VERSION 5.7 ;
  NOWIREEXTENSIONATPIN ON ;
  DIVIDERCHAR "/" ;
  BUSBITCHARS "[]" ;
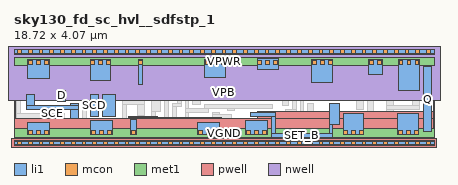
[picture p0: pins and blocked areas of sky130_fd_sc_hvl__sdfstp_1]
MACRO sky130_fd_sc_hvl__sdfstp_1
  CLASS BLOCK ;
  FOREIGN sky130_fd_sc_hvl__sdfstp_1 ;
  ORIGIN 0.000 0.000 ;
  SIZE 18.720 BY 4.070 ;
  PIN CLK
    ANTENNAGATEAREA 0.585000 ;
    PORT
      LAYER li1 ;
        RECT 3.965 1.175 4.525 2.150 ;
    END
  END CLK
  PIN D
    ANTENNAGATEAREA 0.420000 ;
    PORT
      LAYER li1 ;
        RECT 1.945 1.845 2.275 2.355 ;
    END
  END D
  PIN SCD
    ANTENNAGATEAREA 0.420000 ;
    PORT
      LAYER li1 ;
        RECT 3.420 1.175 3.750 2.150 ;
    END
  END SCD
  PIN SCE
    ANTENNAGATEAREA 0.840000 ;
    PORT
      LAYER li1 ;
        RECT 0.565 1.665 0.895 2.165 ;
        RECT 2.525 1.665 2.890 1.780 ;
        RECT 0.565 1.495 2.890 1.665 ;
        RECT 2.525 1.095 2.890 1.495 ;
    END
  END SCE
  PIN SET_B
    ANTENNAGATEAREA 0.840000 ;
    PORT
      LAYER li1 ;
        RECT 10.535 1.175 11.635 1.345 ;
        RECT 11.465 0.435 11.635 1.175 ;
        RECT 14.045 0.810 14.520 1.760 ;
        RECT 14.045 0.435 14.215 0.810 ;
        RECT 11.465 0.265 14.215 0.435 ;
    END
  END SET_B
  PIN VGND
    USE GROUND ;
    PORT
      LAYER li1 ;
        RECT 0.620 0.365 1.570 0.915 ;
        RECT 3.420 0.365 4.370 0.995 ;
        RECT 5.200 0.365 5.450 1.055 ;
        RECT 8.200 0.365 9.150 0.925 ;
        RECT 10.335 0.365 11.285 0.995 ;
        RECT 14.700 0.365 15.590 1.325 ;
        RECT 17.095 0.365 18.045 1.325 ;
      LAYER mcon ;
        RECT 0.650 0.395 0.820 0.565 ;
        RECT 1.010 0.395 1.180 0.565 ;
        RECT 1.370 0.395 1.540 0.565 ;
        RECT 3.450 0.395 3.620 0.565 ;
        RECT 3.810 0.395 3.980 0.565 ;
        RECT 4.170 0.395 4.340 0.565 ;
        RECT 5.230 0.395 5.400 0.565 ;
        RECT 8.230 0.395 8.400 0.565 ;
        RECT 8.590 0.395 8.760 0.565 ;
        RECT 8.950 0.395 9.120 0.565 ;
        RECT 10.365 0.395 10.535 0.565 ;
        RECT 10.725 0.395 10.895 0.565 ;
        RECT 11.085 0.395 11.255 0.565 ;
        RECT 14.700 0.395 14.870 0.565 ;
        RECT 15.060 0.395 15.230 0.565 ;
        RECT 15.420 0.395 15.590 0.565 ;
        RECT 17.125 0.395 17.295 0.565 ;
        RECT 17.485 0.395 17.655 0.565 ;
        RECT 17.845 0.395 18.015 0.565 ;
      LAYER met1 ;
        RECT 0.000 0.255 18.720 0.625 ;
    END
  END VGND
  PIN VNB
    ANTENNADIFFAREA 3.182400 ;
    PORT
      LAYER pwell ;
        RECT 5.110 1.115 6.400 1.165 ;
        RECT 5.110 1.085 9.240 1.115 ;
        RECT 10.865 1.085 18.700 1.415 ;
        RECT 0.020 0.215 18.700 1.085 ;
        RECT -0.130 -0.215 18.850 0.215 ;
      LAYER li1 ;
        RECT 0.000 -0.085 18.720 0.085 ;
      LAYER mcon ;
        RECT 0.155 -0.085 0.325 0.085 ;
        RECT 0.635 -0.085 0.805 0.085 ;
        RECT 1.115 -0.085 1.285 0.085 ;
        RECT 1.595 -0.085 1.765 0.085 ;
        RECT 2.075 -0.085 2.245 0.085 ;
        RECT 2.555 -0.085 2.725 0.085 ;
        RECT 3.035 -0.085 3.205 0.085 ;
        RECT 3.515 -0.085 3.685 0.085 ;
        RECT 3.995 -0.085 4.165 0.085 ;
        RECT 4.475 -0.085 4.645 0.085 ;
        RECT 4.955 -0.085 5.125 0.085 ;
        RECT 5.435 -0.085 5.605 0.085 ;
        RECT 5.915 -0.085 6.085 0.085 ;
        RECT 6.395 -0.085 6.565 0.085 ;
        RECT 6.875 -0.085 7.045 0.085 ;
        RECT 7.355 -0.085 7.525 0.085 ;
        RECT 7.835 -0.085 8.005 0.085 ;
        RECT 8.315 -0.085 8.485 0.085 ;
        RECT 8.795 -0.085 8.965 0.085 ;
        RECT 9.275 -0.085 9.445 0.085 ;
        RECT 9.755 -0.085 9.925 0.085 ;
        RECT 10.235 -0.085 10.405 0.085 ;
        RECT 10.715 -0.085 10.885 0.085 ;
        RECT 11.195 -0.085 11.365 0.085 ;
        RECT 11.675 -0.085 11.845 0.085 ;
        RECT 12.155 -0.085 12.325 0.085 ;
        RECT 12.635 -0.085 12.805 0.085 ;
        RECT 13.115 -0.085 13.285 0.085 ;
        RECT 13.595 -0.085 13.765 0.085 ;
        RECT 14.075 -0.085 14.245 0.085 ;
        RECT 14.555 -0.085 14.725 0.085 ;
        RECT 15.035 -0.085 15.205 0.085 ;
        RECT 15.515 -0.085 15.685 0.085 ;
        RECT 15.995 -0.085 16.165 0.085 ;
        RECT 16.475 -0.085 16.645 0.085 ;
        RECT 16.955 -0.085 17.125 0.085 ;
        RECT 17.435 -0.085 17.605 0.085 ;
        RECT 17.915 -0.085 18.085 0.085 ;
        RECT 18.395 -0.085 18.565 0.085 ;
      LAYER met1 ;
        RECT 0.000 -0.115 18.720 0.115 ;
    END
  END VNB
  PIN VPB
    ANTENNADIFFAREA 3.182400 ;
    PORT
      LAYER nwell ;
        RECT -0.330 1.885 19.050 4.485 ;
      LAYER li1 ;
        RECT 0.000 3.985 18.720 4.155 ;
      LAYER mcon ;
        RECT 0.155 3.985 0.325 4.155 ;
        RECT 0.635 3.985 0.805 4.155 ;
        RECT 1.115 3.985 1.285 4.155 ;
        RECT 1.595 3.985 1.765 4.155 ;
        RECT 2.075 3.985 2.245 4.155 ;
        RECT 2.555 3.985 2.725 4.155 ;
        RECT 3.035 3.985 3.205 4.155 ;
        RECT 3.515 3.985 3.685 4.155 ;
        RECT 3.995 3.985 4.165 4.155 ;
        RECT 4.475 3.985 4.645 4.155 ;
        RECT 4.955 3.985 5.125 4.155 ;
        RECT 5.435 3.985 5.605 4.155 ;
        RECT 5.915 3.985 6.085 4.155 ;
        RECT 6.395 3.985 6.565 4.155 ;
        RECT 6.875 3.985 7.045 4.155 ;
        RECT 7.355 3.985 7.525 4.155 ;
        RECT 7.835 3.985 8.005 4.155 ;
        RECT 8.315 3.985 8.485 4.155 ;
        RECT 8.795 3.985 8.965 4.155 ;
        RECT 9.275 3.985 9.445 4.155 ;
        RECT 9.755 3.985 9.925 4.155 ;
        RECT 10.235 3.985 10.405 4.155 ;
        RECT 10.715 3.985 10.885 4.155 ;
        RECT 11.195 3.985 11.365 4.155 ;
        RECT 11.675 3.985 11.845 4.155 ;
        RECT 12.155 3.985 12.325 4.155 ;
        RECT 12.635 3.985 12.805 4.155 ;
        RECT 13.115 3.985 13.285 4.155 ;
        RECT 13.595 3.985 13.765 4.155 ;
        RECT 14.075 3.985 14.245 4.155 ;
        RECT 14.555 3.985 14.725 4.155 ;
        RECT 15.035 3.985 15.205 4.155 ;
        RECT 15.515 3.985 15.685 4.155 ;
        RECT 15.995 3.985 16.165 4.155 ;
        RECT 16.475 3.985 16.645 4.155 ;
        RECT 16.955 3.985 17.125 4.155 ;
        RECT 17.435 3.985 17.605 4.155 ;
        RECT 17.915 3.985 18.085 4.155 ;
        RECT 18.395 3.985 18.565 4.155 ;
      LAYER met1 ;
        RECT 0.000 3.955 18.720 4.185 ;
    END
  END VPB
  PIN VPWR
    USE POWER ;
    PORT
      LAYER li1 ;
        RECT 0.620 2.885 1.570 3.705 ;
        RECT 3.420 2.805 4.315 3.705 ;
        RECT 5.545 2.625 5.725 3.705 ;
        RECT 8.495 2.925 9.445 3.705 ;
        RECT 10.835 3.285 11.785 3.755 ;
        RECT 13.265 2.675 14.215 3.705 ;
        RECT 15.815 3.045 16.405 3.705 ;
        RECT 17.135 2.355 18.080 3.705 ;
      LAYER mcon ;
        RECT 0.650 3.505 0.820 3.675 ;
        RECT 1.010 3.505 1.180 3.675 ;
        RECT 1.370 3.505 1.540 3.675 ;
        RECT 3.420 3.505 3.590 3.675 ;
        RECT 3.780 3.505 3.950 3.675 ;
        RECT 4.140 3.505 4.310 3.675 ;
        RECT 5.550 3.505 5.720 3.675 ;
        RECT 8.525 3.505 8.695 3.675 ;
        RECT 8.885 3.505 9.055 3.675 ;
        RECT 9.245 3.505 9.415 3.675 ;
        RECT 10.865 3.505 11.035 3.675 ;
        RECT 11.225 3.505 11.395 3.675 ;
        RECT 11.585 3.505 11.755 3.675 ;
        RECT 13.295 3.505 13.465 3.675 ;
        RECT 13.655 3.505 13.825 3.675 ;
        RECT 14.015 3.505 14.185 3.675 ;
        RECT 15.845 3.505 16.015 3.675 ;
        RECT 16.205 3.505 16.375 3.675 ;
        RECT 17.160 3.505 17.330 3.675 ;
        RECT 17.520 3.505 17.690 3.675 ;
        RECT 17.880 3.505 18.050 3.675 ;
      LAYER met1 ;
        RECT 0.000 3.445 18.720 3.815 ;
    END
  END VPWR
  PIN Q
    ANTENNADIFFAREA 0.478750 ;
    PORT
      LAYER li1 ;
        RECT 18.260 0.495 18.610 3.395 ;
    END
  END Q
  OBS
      LAYER li1 ;
        RECT 4.495 3.635 5.365 3.805 ;
        RECT 0.110 2.705 0.440 3.285 ;
        RECT 2.380 3.055 2.710 3.305 ;
        RECT 2.380 2.885 3.240 3.055 ;
        RECT 0.110 2.535 2.890 2.705 ;
        RECT 0.110 1.315 0.280 2.535 ;
        RECT 2.635 2.015 2.890 2.535 ;
        RECT 3.070 2.625 3.240 2.885 ;
        RECT 4.495 2.625 4.665 3.635 ;
        RECT 3.070 2.455 4.665 2.625 ;
        RECT 0.110 1.095 2.255 1.315 ;
        RECT 0.110 0.515 0.440 1.095 ;
        RECT 3.070 0.915 3.240 2.455 ;
        RECT 4.845 1.905 5.015 3.455 ;
        RECT 5.195 2.445 5.365 3.635 ;
        RECT 5.905 3.635 7.095 3.805 ;
        RECT 5.905 2.445 6.075 3.635 ;
        RECT 5.195 2.275 6.075 2.445 ;
        RECT 6.255 2.095 6.530 3.455 ;
        RECT 4.845 1.735 5.835 1.905 ;
        RECT 4.845 0.975 5.015 1.735 ;
        RECT 5.505 1.235 5.835 1.735 ;
        RECT 6.140 1.425 6.530 2.095 ;
        RECT 6.710 2.675 7.095 3.635 ;
        RECT 7.275 3.355 8.305 3.525 ;
        RECT 2.380 0.745 3.240 0.915 ;
        RECT 2.380 0.495 2.710 0.745 ;
        RECT 4.650 0.515 5.015 0.975 ;
        RECT 5.630 0.435 5.800 1.235 ;
        RECT 6.140 1.055 6.310 1.425 ;
        RECT 5.980 0.675 6.310 1.055 ;
        RECT 6.710 1.025 6.880 2.675 ;
        RECT 7.275 1.775 7.445 3.355 ;
        RECT 6.550 0.615 6.880 1.025 ;
        RECT 7.060 1.605 7.445 1.775 ;
        RECT 7.625 2.675 7.955 3.175 ;
        RECT 8.135 2.745 8.305 3.355 ;
        RECT 9.625 3.105 10.655 3.275 ;
        RECT 9.625 2.745 9.795 3.105 ;
        RECT 10.485 2.935 12.180 3.105 ;
        RECT 7.060 0.435 7.230 1.605 ;
        RECT 7.625 1.525 7.795 2.675 ;
        RECT 8.135 2.575 9.795 2.745 ;
        RECT 8.135 2.225 8.410 2.575 ;
        RECT 9.975 2.395 10.305 2.925 ;
        RECT 8.790 2.225 10.305 2.395 ;
        RECT 11.905 2.395 12.180 2.935 ;
        RECT 12.360 2.845 12.690 3.755 ;
        RECT 14.395 3.335 15.625 3.505 ;
        RECT 12.360 2.675 12.920 2.845 ;
        RECT 11.905 2.225 12.570 2.395 ;
        RECT 7.975 1.875 12.220 2.045 ;
        RECT 7.975 1.705 8.305 1.875 ;
        RECT 8.485 1.525 11.525 1.695 ;
        RECT 11.970 1.685 12.220 1.875 ;
        RECT 7.625 1.355 8.655 1.525 ;
        RECT 9.520 1.455 9.850 1.525 ;
        RECT 12.400 1.505 12.570 2.225 ;
        RECT 7.625 1.025 7.795 1.355 ;
        RECT 8.835 1.275 9.165 1.345 ;
        RECT 12.095 1.335 12.570 1.505 ;
        RECT 12.750 2.110 12.920 2.675 ;
        RECT 14.395 2.495 14.565 3.335 ;
        RECT 13.710 2.290 14.565 2.495 ;
        RECT 14.745 2.175 15.075 3.155 ;
        RECT 15.295 2.865 15.625 3.335 ;
        RECT 15.295 2.695 16.020 2.865 ;
        RECT 14.745 2.110 15.585 2.175 ;
        RECT 12.750 1.940 15.585 2.110 ;
        RECT 8.835 1.105 9.700 1.275 ;
        RECT 7.410 0.525 7.795 1.025 ;
        RECT 9.370 0.515 9.700 1.105 ;
        RECT 12.095 0.785 12.265 1.335 ;
        RECT 12.750 1.155 12.920 1.940 ;
        RECT 12.445 0.965 12.920 1.155 ;
        RECT 13.100 0.785 13.350 1.745 ;
        RECT 15.255 1.505 15.585 1.940 ;
        RECT 15.770 0.825 16.020 2.695 ;
        RECT 16.585 2.355 16.955 3.145 ;
        RECT 16.585 1.675 16.915 2.355 ;
        RECT 17.750 1.675 18.080 2.175 ;
        RECT 16.585 1.505 18.080 1.675 ;
        RECT 16.585 0.825 16.915 1.505 ;
        RECT 12.095 0.615 13.350 0.785 ;
        RECT 5.630 0.265 7.230 0.435 ;
  END
END sky130_fd_sc_hvl__sdfstp_1
END LIBRARY

